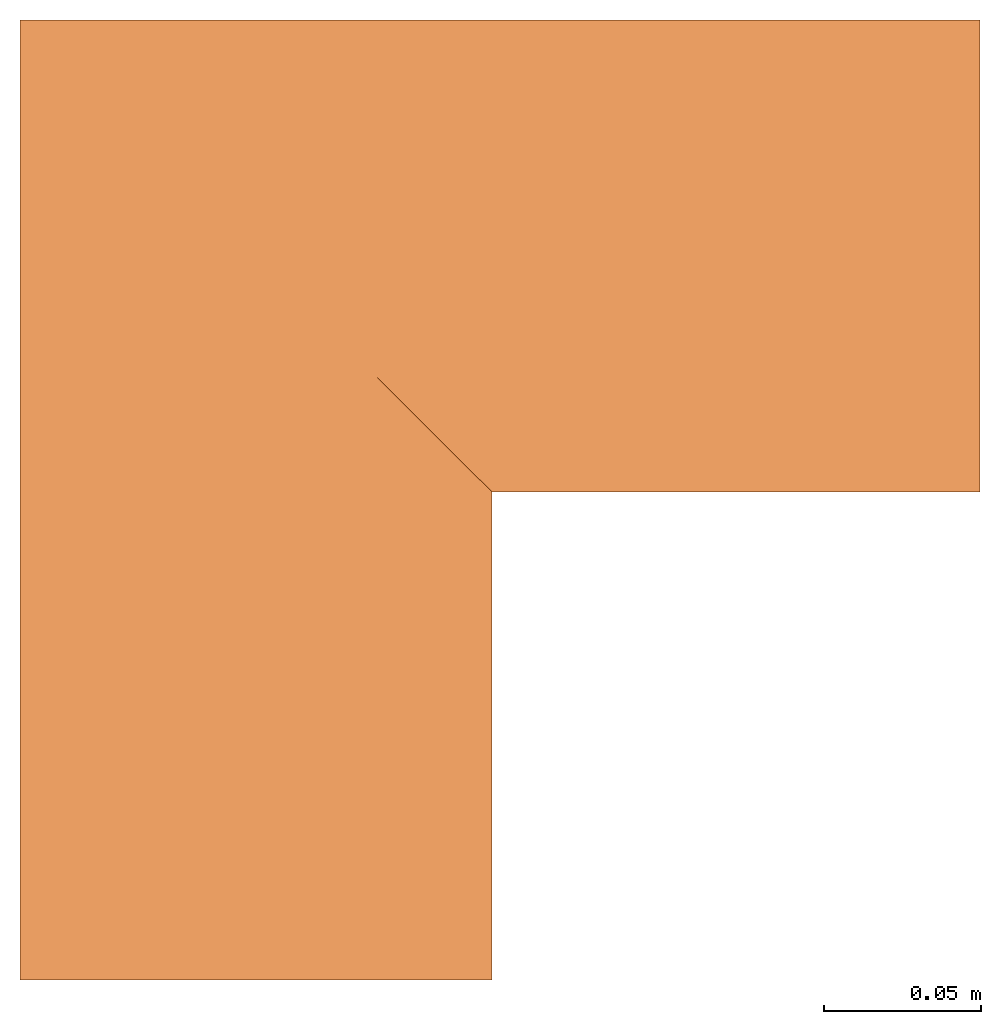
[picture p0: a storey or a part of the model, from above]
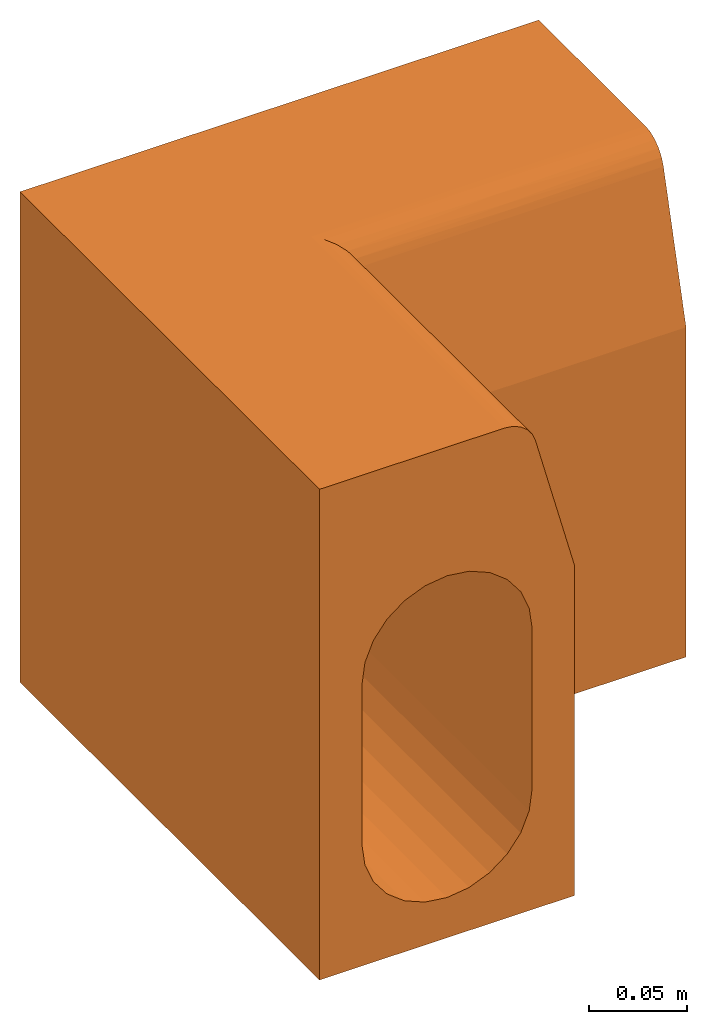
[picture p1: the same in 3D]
Properties of the parts of a building model (IFC2X3)

# File
Description: ViewDefinition [CoordinationView]
File name: 4991 - Internal angle.ifc
Time: 2013-09-12T12:54:12
Written by: Autodesk Revit 2013
Made in: 20120221_2030(x64)

# IfcProject, Project Number
LongName: Project Name; Phase: Project Status

# IfcSite, Default
RefLatitude: 42, 21, 30, 344238; RefLongitude: -71, -3, -35, -194702; RefElevation: 0 mm

# IfcBuilding
Pset_BuildingCommon - NumberOfStoreys: 2
Other - Project Issue Date: Issue Date; Project Number: Project Number; Project Name: Project Name; Project Address: Enter address here; Client Name: Owner; Project Status: Project Status

# IfcBuildingStorey (2)
Constraints - Elevation Base: 0
Graphics - Line Pattern: Center; Symbol: M_Level Head - Circle: M_Level Head - Circle; Symbol at End 1 Default: no; Color: 0; Line Weight: 1; Symbol at End 2 Default: yes
Identity Data - Building Story: yes; Structural: no
Dimensions - Computation Height: 0 mm
Name | LongName = Name | Elevation (mm) = Constraints, Elevation (mm)
T.O. Fnd. Wall | T.O. Fnd. Wall | -300
Level 1 | Level 1 | 0

# IfcBuildingElementProxy: 4991 - Internal angle, Civil-Drainage-Channel-ACO-KerbDrain-HB305 Part 2:4991 - Internal angle:4991 - Internal angle:263456
In: T.O. Fnd. Wall
Material: ACO Polymer Concrete.
Other - Revision: 1; CreatedBy: www.aco.co.uk
Materials and Finishes - End Cap Colour: N/A; End Cap Material: N/A; Channel Colour: Grey; Access Cover/Frame Colour: N/A; Channel Material: Vienite® Synthetic Resin Concrete; Connection Pipe Material Colour: N/A; Access Cover/Frame Material: N/A; Access Cover/Frame Finish: N/A; Connection Pipe Material: N/A
Data - Product Standard: BS EN 1433:2002, CE marked, Kitemarked; Drainage Slot Intake area: N/A; Load Class: A 15 - D 400; Connection Pipe O.D: N/A; Concrete Surround Volume - Load Class A 15 - D 400 - Concrete Pavement: N/A; Invert Depth: 280mm; Product Dimensions: 305mm x 150mm x 305mm (LxWxH); Drainage Slot Width: N/A; Installation - Concrete Grade: Refer to brochure; Hydraulic Performance: http://www.aco.co.uk/download.php?id=120; Channel C.S.A: 0.02m²; Product Weight: 24.7 Kg; Concrete Surround Volume - Load Class A 15 - D 400 - Grass or Asphalt Pavement: N/A; ACO Hydraulic Design Software: http://www.acodesign.co.uk
Phasing - Phase Created: Phase 1
Constraints - Moves With Nearby Elements: no; Level: Level: Level 1
Dimensions - Volume: 12378038 mm3; Mitre Void End: -5205 mm; Curved RH Void Start: -2980 mm; Mite Long Side Length: 500 mm; Void_Width: 100 mm; 6m Radius unit void Start: -6000 mm; Mitre Void Start: -5200 mm; Curved RH Void End: -3000 mm; Void L End: 0 mm; 1.8m Radius unit Void Start: -4800 mm; Quadrant void End: 2620 mm; Quadrant void Start: 2600 mm; Curved LH Void End: 3010 mm; 1.8m Radius Unit void End: -4805 mm; Curved LH Void Start: 3000 mm; Flush Drainable Centre Stone Void Start: -4500 mm; Void_Length: 305 mm; mitre small length: 487 mm; 6m Radius Unit Void end: -6005 mm; Staright Void Depth: -180 mm; Void L Start: -180 mm; Flush Drainable Centre Stone Void End: -4505 mm; Straight Void Depth: 0 mm
Pset_BuildingElementProxyCommon - Reference: 4991 - Internal angle
General - SerialNumber: 0.000000; TagNumber: 0.000000
Identity Data - Telephone: +44 (0)1462 816666; Maintenance guidelines: http://www.aco.co.uk/download.php?id=120; Model Description: Combined kerb and drainage system; Address: ACO Business Park, Hitchin Road, Shefford, Bedfordshire, United Kingdom SG17 5TE; Fax: +44 (0)1462 815895; Price: POA - contact ACO; Assembly Description: Rain Water Drainage; Product Page URL: http://www.aco.co.uk/product_detail.php?id=3; URL: www.aco.co.uk; OmniClass Title: Rainwater Removal; Installation guidelines: http://www.aco.co.uk/download.php?id=120; e-mail Technical: technical@aco.co.uk; Product Code: 4991; Product brochure: http://www.aco.co.uk/download.php?id=120; Assembly Code: D2040; Type Comments: ACO KerbDrain HB305 half battered 90 degree internal angle 305mm long; OmniClass Number: 23.70.50.24; Manufacturer: ACO Technologies plc - ACO Water Management Division; e-mail Sales: customersupport@aco.co.uk; Cost: 0; Model: ACO KerbDrain HB305
Construction - KDHB305 RH drop kerb-4999: no; KDHB305 internal_angle: yes; KDHB305 6m _external_radius: no; LH drop kerb- 6m ext rad: no; KDHB305 1.8m_radius: no; KDHB305 7-6m external_mitre: no; KDHB305 25-11m external_mitre: no; KDHB305 25-11m internal_mitre: no; KDHB305_quadrant: no; KDHB305 10-8m_external_mitre: no; flush drainable centre stone: no
Green Building Properties - Access Cover/Frame Recyclable: N/A; End Cap Recycled Material Content: N/A; Channel Recycled Material Content: 20% minimum; Channel Recyclable: Fully recyclable; Access Cover/Frame Recycled Material Content: N/A; End Cap Recyclable: N/A

# IfcOpeningElement: Recess (7)
In: Level 1
Constraints - Level: Level: Level 1; Height Offset From Level: 0 mm; Room Bounding: yes; Related to Mass: no
Dimensions - Thickness: 400 mm; Perimeter: 21157.2 mm; Area: 27858925 mm2; Volume: 11131222135 mm3
Phasing - Phase Created: Phase 1
Structural - Enable Analytical Model: no; Structural: no
Analytical Properties - Absorptance: 0.1; Roughness: 1
Graphics - Coarse Scale Fill Color: 0
Construction - Default Thickness: 400 mm; Function: 0

# IfcSlab: Floor:Generic Floor - 400mm, Floor:Generic Floor - 400mm:184025
In: Level 1
PredefinedType: FLOOR; Material: Default Floor 400 mm
Constraints - Level: Level: Level 1; Height Offset From Level: 0 mm; Room Bounding: yes; Related to Mass: no
Dimensions - Thickness: 400 mm; Perimeter: 21157.2 mm; Area: 27858925 mm2; Volume: 11131222135 mm3
Phasing - Phase Created: Phase 1
Structural - Enable Analytical Model: no; Structural: no
Pset_SlabCommon - Reference: Generic Floor - 400mm; IsExternal: no; LoadBearing: yes
Analytical Properties - Absorptance: 0.1; Roughness: 1
Graphics - Coarse Scale Fill Color: 0
Construction - Default Thickness: 400 mm; Function: 0
